# LEF Technology file for openrule1um
#     Copyright (c) Ckristian Duran
# See LICENSE for details

VERSION 5.7 ;
BUSBITCHARS "[]" ;
DIVIDERCHAR "/" ;

UNITS
  TIME NANOSECONDS 1 ;
  CAPACITANCE PICOFARADS 1 ;
  RESISTANCE OHMS 1 ;
  DATABASE MICRONS 1000 ;
END UNITS

MANUFACTURINGGRID 0.250 ;
USEMINSPACING OBS OFF ;

PROPERTYDEFINITIONS
  LAYER LEF58_TYPE STRING ;
END PROPERTYDEFINITIONS

# High density, single height
SITE core
  SYMMETRY Y ;
  CLASS CORE ;
  SIZE 3.000 BY 29.000 ;
END core

LAYER DM_via1
  TYPE IMPLANT ;
  SPACING 1.0 ;
  WIDTH 1.0 ;
END DM_via1

LAYER DM_via2
  TYPE IMPLANT ;
  SPACING 1.0 ;
  WIDTH 1.0 ;
END DM_via2

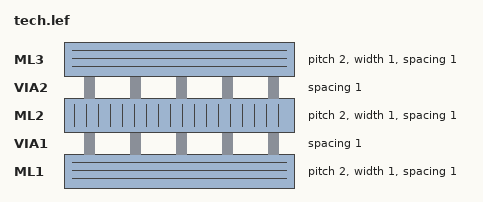
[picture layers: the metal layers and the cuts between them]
LAYER ML1
  TYPE ROUTING ;
  DIRECTION HORIZONTAL ;
  PITCH 2.0 ;
#  PITCH 3.0 ;
  OFFSET 0.5 ;
  WIDTH 1.0 ;
  AREA 0.0 ;
  SPACING  1.0 ;
  CAPACITANCE CPERSQDIST 0.0007630 ;
  EDGECAPACITANCE 0.0000339 ;
  RESISTANCE RPERSQ 0.0914 ;
END ML1

LAYER VIA1
  TYPE CUT ;
  SPACING 1.0 ;
#  SPACING 1.0 LAYER VIA2 STACK ;
END VIA1

LAYER ML2
  TYPE ROUTING ;
  DIRECTION VERTICAL ;
  PITCH 2.0 ;
#  PITCH 3.0 ;
  OFFSET 0.5 ;
  WIDTH 1.0 ;
  AREA 0.0 ;
  SPACING  1.0 ;
  CAPACITANCE CPERSQDIST 0.0007630 ;
  EDGECAPACITANCE 0.0000339 ;
  RESISTANCE RPERSQ 0.0914 ;
END ML2

LAYER VIA2
  TYPE CUT ;
  SPACING 1.0 ;
  SPACING 1.0 LAYER VIA1 STACK ;
END VIA2

LAYER ML3
  TYPE ROUTING ;
  DIRECTION HORIZONTAL ;
  PITCH 2.0 ;
#  PITCH 3.0 ;
  OFFSET 0.5 ;
  WIDTH 1.0 ;
  AREA 0.0 ;
  SPACING  1.0 ;
  CAPACITANCE CPERSQDIST 0.0007630 ;
  EDGECAPACITANCE 0.0000339 ;
  RESISTANCE RPERSQ 0.0914 ;
END ML3

VIA VIA1_C DEFAULT
  LAYER ML1 ;
    RECT -1.0 -1.0 1.0 1.0 ;
  LAYER ML2 ;
    RECT -1.0 -1.0 1.0 1.0 ;
  LAYER VIA1 ;
    RECT -0.5 -0.5 0.5 0.5 ;
#  LAYER DM_via1 ;
#    RECT -1.0 -1.0 1.0 1.0 ;
END VIA1_C

VIA VIA2_C DEFAULT
  LAYER ML2 ;
    RECT -1.0 -1.0 1.0 1.0 ;
  LAYER ML3 ;
    RECT -1.0 -1.0 1.0 1.0 ;
  LAYER VIA2 ;
    RECT -0.5 -0.5 0.5 0.5 ;
#  LAYER DM_via2 ;
#    RECT -1.0 -1.0 1.0 1.0 ;
END VIA2_C

VIARULE VIA1_RULE GENERATE
  LAYER ML1 ;
    ENCLOSURE 0.5 0.5 ;
  LAYER ML2 ;
    ENCLOSURE 0.5 0.5 ;
#  LAYER DM_via1 ;
#    ENCLOSURE 0.5 0.5 ;
  LAYER VIA1 ;
    RECT -0.5 -0.5 0.5 0.5 ;
    SPACING 1.0 BY 1.0 ;
END VIA1_RULE

VIARULE VIA2_RULE GENERATE
  LAYER ML2 ;
    ENCLOSURE 0.5 0.5 ;
  LAYER ML3 ;
    ENCLOSURE 0.5 0.5 ;
#  LAYER DM_via2 ;
#    ENCLOSURE 0.5 0.5 ;
  LAYER VIA2 ;
    RECT -0.5 -0.5 0.5 0.5 ;
    SPACING 1.0 BY 1.0 ;
END VIA2_RULE

END LIBRARY

